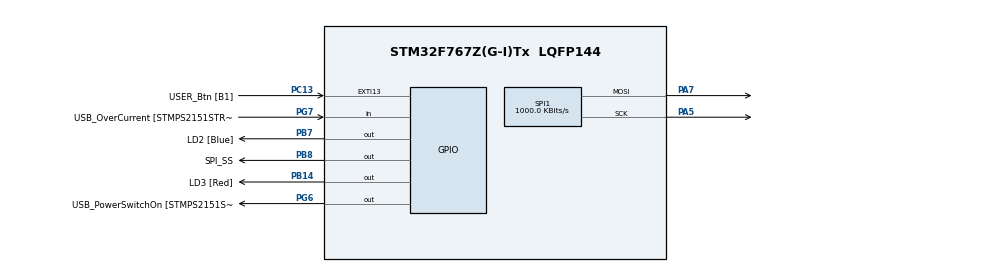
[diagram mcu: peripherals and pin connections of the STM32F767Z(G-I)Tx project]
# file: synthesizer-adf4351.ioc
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Mcu.Family=STM32F7
Mcu.Name=STM32F767Z(G-I)Tx
Mcu.Package=LQFP144
NVIC.PriorityGroup=NVIC_PRIORITYGROUP_4
PA1.GPIO_Label=RMII_REF_CLK [LAN8742A-CZ-TR_REFCLK0]
PA1.Signal=ETH_REF_CLK
PA10.GPIO_Label=USB_ID
PA10.Signal=USB_OTG_FS_ID
PA11.GPIO_Label=USB_DM
PA11.Signal=USB_OTG_FS_DM
PA12.GPIO_Label=USB_DP
PA12.Signal=USB_OTG_FS_DP
PA13.GPIO_Label=TMS
PA13.Signal=SYS_JTMS-SWDIO
PA14.GPIO_Label=TCK
PA14.Signal=SYS_JTCK-SWCLK
PA2.GPIO_Label=RMII_MDIO [LAN8742A-CZ-TR_MDIO]
PA2.Signal=ETH_MDIO
PA5.Mode=TX_Only_Simplex_Unidirect_Master
PA5.Signal=SPI1_SCK
PA7.Mode=TX_Only_Simplex_Unidirect_Master
PA7.Signal=SPI1_MOSI
PA8.GPIO_Label=USB_SOF [TP1]
PA8.Signal=USB_OTG_FS_SOF
PA9.GPIO_Label=USB_VBUS
PA9.Signal=USB_OTG_FS_VBUS
PB13.GPIO_Label=RMII_TXD1 [LAN8742A-CZ-TR_TXD1]
PB13.Signal=ETH_TXD1
PB14.GPIO_Label=LD3 [Red]
PB14.Signal=GPIO_Output
PB3.GPIO_Label=SW0
PB3.Signal=SYS_JTDO-SWO
PB7.GPIO_Label=LD2 [Blue]
PB7.Signal=GPIO_Output
PB8.GPIO_Label=SPI_SS
PB8.Signal=GPIO_Output
PC1.GPIO_Label=RMII_MDC [LAN8742A-CZ-TR_MDC]
PC1.Signal=ETH_MDC
PC13.GPIO_Label=USER_Btn [B1]
PC13.Signal=GPXTI13
PC14/OSC32_IN.Signal=RCC_OSC32_IN
PC15/OSC32_OUT.Signal=RCC_OSC32_OUT
PC4.GPIO_Label=RMII_RXD0 [LAN8742A-CZ-TR_RXD0]
PC4.Signal=ETH_RXD0
PC5.GPIO_Label=RMII_RXD1 [LAN8742A-CZ-TR_RXD1]
PC5.Signal=ETH_RXD1
PD8.GPIO_Label=STLK_RX [STM32F103CBT6_PA3]
PD8.Signal=USART3_TX
PD9.GPIO_Label=STLK_TX [STM32F103CBT6_PA2]
PD9.Signal=USART3_RX
PG11.GPIO_Label=RMII_TX_EN [LAN8742A-CZ-TR_TXEN]
PG11.Signal=ETH_TX_EN
PG13.GPIO_Label=RMII_TXD0 [LAN8742A-CZ-TR_TXD0]
PG13.Signal=ETH_TXD0
PG6.GPIO_Label=USB_PowerSwitchOn [STMPS2151STR_EN]
PG6.Signal=GPIO_Output
PG7.GPIO_Label=USB_OverCurrent [STMPS2151STR_FAULT]
PG7.Signal=GPIO_Input
PH0/OSC_IN.GPIO_Label=MCO [STM32F103CBT6_PA8]
PH0/OSC_IN.Mode=HSE-External-Clock-Source
PH0/OSC_IN.Signal=RCC_OSC_IN
PH1/OSC_OUT.Mode=HSE-External-Clock-Source
PH1/OSC_OUT.Signal=RCC_OSC_OUT
ProjectManager.HeapSize=0x200
ProjectManager.StackSize=0x400
ProjectManager.TargetToolchain=Makefile
RCC.48MHZClocksFreq_Value=24000000
RCC.AHBFreq_Value=8000000
RCC.APB1CLKDivider=RCC_HCLK_DIV2
RCC.APB1Freq_Value=4000000
RCC.APB1TimFreq_Value=8000000
RCC.APB2Freq_Value=8000000
RCC.APB2TimFreq_Value=8000000
RCC.CortexFreq_Value=8000000
RCC.HCLKFreq_Value=8000000
RCC.HSE_VALUE=8000000
RCC.HSI_VALUE=16000000
RCC.LSE_VALUE=32768
RCC.PLLMUL=RCC_PLL_MUL9
RCC.PLLSourceVirtual=RCC_PLLSOURCE_HSE
RCC.PRESCALERUSB=RCC_USBCLKSOURCE_PLL_DIV1_5
RCC.SYSCLKFreq_VALUE=8000000
RCC.SYSCLKSource=RCC_SYSCLKSOURCE_HSE
RCC.SYSCLKSourceVirtual=RCC_SYSCLKSOURCE_PLLCLK
RCC.USBFreq_Value=48000000
RCC.VCOOutputFreq_Value=96000000
SPI1.BaudRatePrescaler=SPI_BAUDRATEPRESCALER_8
SPI1.CalculateBaudRate=1000.0 KBits/s
SPI1.DataSize=SPI_DATASIZE_8BIT
SPI1.Direction=SPI_DIRECTION_2LINES
SPI1.FirstBit=SPI_FIRSTBIT_MSB
SPI1.Mode=SPI_MODE_MASTER
SPI1.TIMode=SPI_TIMODE_DISABLE
SPI1.VirtualType=VM_MASTER
board=NUCLEO-F767ZI

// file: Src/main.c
/**
  ******************************************************************************
  * File Name          : main.c
  * Description        : Main program body
  ******************************************************************************
  ** This notice applies to any and all portions of this file
  * that are not between comment pairs USER CODE BEGIN and
  * USER CODE END. Other portions of this file, whether
  * inserted by the user or by software development tools
  * are owned by their respective copyright owners.
  *
  * COPYRIGHT(c) 2017 STMicroelectronics
  *
  * Redistribution and use in source and binary forms, with or without modification,
  * are permitted provided that the following conditions are met:
  *   1. Redistributions of source code must retain the above copyright notice,
  *      this list of conditions and the following disclaimer.
  *   2. Redistributions in binary form must reproduce the above copyright notice,
  *      this list of conditions and the following disclaimer in the documentation
  *      and/or other materials provided with the distribution.
  *   3. Neither the name of STMicroelectronics nor the names of its contributors
  *      may be used to endorse or promote products derived from this software
  *      without specific prior written permission.
  *
  * THIS SOFTWARE IS PROVIDED BY THE COPYRIGHT HOLDERS AND CONTRIBUTORS "AS IS"
  * AND ANY EXPRESS OR IMPLIED WARRANTIES, INCLUDING, BUT NOT LIMITED TO, THE
  * IMPLIED WARRANTIES OF MERCHANTABILITY AND FITNESS FOR A PARTICULAR PURPOSE ARE
  * DISCLAIMED. IN NO EVENT SHALL THE COPYRIGHT HOLDER OR CONTRIBUTORS BE LIABLE
  * FOR ANY DIRECT, INDIRECT, INCIDENTAL, SPECIAL, EXEMPLARY, OR CONSEQUENTIAL
  * DAMAGES (INCLUDING, BUT NOT LIMITED TO, PROCUREMENT OF SUBSTITUTE GOODS OR
  * SERVICES; LOSS OF USE, DATA, OR PROFITS; OR BUSINESS INTERRUPTION) HOWEVER
  * CAUSED AND ON ANY THEORY OF LIABILITY, WHETHER IN CONTRACT, STRICT LIABILITY,
  * OR TORT (INCLUDING NEGLIGENCE OR OTHERWISE) ARISING IN ANY WAY OUT OF THE USE
  * OF THIS SOFTWARE, EVEN IF ADVISED OF THE POSSIBILITY OF SUCH DAMAGE.
  *
  ******************************************************************************
  */
#include "main.h"
#include "stm32f7xx_hal.h"

SPI_HandleTypeDef hspi1;

/* USER CODE BEGIN PV */
/* Private variables ---------------------------------------------------------*/

/* USER CODE END PV */

void SystemClock_Config(void);
static void MX_GPIO_Init(void);
static void MX_SPI1_Init(void);

/* USER CODE BEGIN PFP */
/* Private function prototypes -----------------------------------------------*/

static void synthesizer_ss_high() {
  HAL_GPIO_WritePin(SPI_SS_GPIO_Port, SPI_SS_Pin, GPIO_PIN_SET);
}

static void synthesizer_ss_low() {
  HAL_GPIO_WritePin(SPI_SS_GPIO_Port, SPI_SS_Pin, GPIO_PIN_RESET);
}

static void synthesizer_send_register(uint32_t data) {
  synthesizer_ss_low();
  HAL_SPI_Transmit(&hspi1, (uint8_t *)data, 32, 5 * 1000);
  synthesizer_ss_high();
}

static void synthesizer_set_registers(
  uint32_t r0,
  uint32_t r1,
  uint32_t r2,
  uint32_t r3,
  uint32_t r4,
  uint32_t r5) {

  synthesizer_send_register(r5);
  // synthesizer_send_register(r4);
  // synthesizer_send_register(r3);
  // synthesizer_send_register(r2);
  // synthesizer_send_register(r1);
  // synthesizer_send_register(r0);
}

/* USER CODE END PFP */

int main(void)
{

  /* MCU Configuration----------------------------------------------------------*/

  /* Reset of all peripherals, Initializes the Flash interface and the Systick. */
  HAL_Init();

  /* Configure the system clock */
  SystemClock_Config();

  /* Initialize all configured peripherals */
  MX_GPIO_Init();
  MX_SPI1_Init();

  /* USER CODE BEGIN 2 */

  // default high
  synthesizer_ss_high();

  /* USER CODE END 2 */

  /* Infinite loop */
  while (1)
  {

  /* USER CODE BEGIN 3 */

    synthesizer_set_registers(
      0x0400000,
      0x8008011,
      0x0004e42,
      0x00004b3,
      0x0ec803c,
      0x0580005);

    HAL_Delay(1);
  }
  /* USER CODE END 3 */

}

/** System Clock Configuration
*/
void SystemClock_Config(void)
{

  RCC_OscInitTypeDef RCC_OscInitStruct;
  RCC_ClkInitTypeDef RCC_ClkInitStruct;

    /**Configure the main internal regulator output voltage
    */
  __HAL_RCC_PWR_CLK_ENABLE();

  __HAL_PWR_VOLTAGESCALING_CONFIG(PWR_REGULATOR_VOLTAGE_SCALE3);

    /**Initializes the CPU, AHB and APB busses clocks
    */
  RCC_OscInitStruct.OscillatorType = RCC_OSCILLATORTYPE_HSE;
  RCC_OscInitStruct.HSEState = RCC_HSE_BYPASS;
  RCC_OscInitStruct.PLL.PLLState = RCC_PLL_NONE;
  if (HAL_RCC_OscConfig(&RCC_OscInitStruct) != HAL_OK)
  {
    _Error_Handler(__FILE__, __LINE__);
  }

    /**Initializes the CPU, AHB and APB busses clocks
    */
  RCC_ClkInitStruct.ClockType = RCC_CLOCKTYPE_HCLK|RCC_CLOCKTYPE_SYSCLK
                              |RCC_CLOCKTYPE_PCLK1|RCC_CLOCKTYPE_PCLK2;
  RCC_ClkInitStruct.SYSCLKSource = RCC_SYSCLKSOURCE_HSE;
  RCC_ClkInitStruct.AHBCLKDivider = RCC_SYSCLK_DIV256;
  RCC_ClkInitStruct.APB1CLKDivider = RCC_HCLK_DIV2;
  RCC_ClkInitStruct.APB2CLKDivider = RCC_HCLK_DIV1;

  if (HAL_RCC_ClockConfig(&RCC_ClkInitStruct, FLASH_LATENCY_0) != HAL_OK)
  {
    _Error_Handler(__FILE__, __LINE__);
  }

    /**Configure the Systick interrupt time
    */
  HAL_SYSTICK_Config(HAL_RCC_GetHCLKFreq()/1000);

    /**Configure the Systick
    */
  HAL_SYSTICK_CLKSourceConfig(SYSTICK_CLKSOURCE_HCLK);

  /* SysTick_IRQn interrupt configuration */
  HAL_NVIC_SetPriority(SysTick_IRQn, 0, 0);
}

/* SPI1 init function */
static void MX_SPI1_Init(void)
{

  /* SPI1 parameter configuration*/
  hspi1.Instance = SPI1;
  hspi1.Init.Mode = SPI_MODE_MASTER;
  hspi1.Init.Direction = SPI_DIRECTION_2LINES;
  hspi1.Init.DataSize = SPI_DATASIZE_8BIT;
  hspi1.Init.CLKPolarity = SPI_POLARITY_LOW;
  hspi1.Init.CLKPhase = SPI_PHASE_1EDGE;
  hspi1.Init.NSS = SPI_NSS_SOFT;
  hspi1.Init.BaudRatePrescaler = SPI_BAUDRATEPRESCALER_2;
  hspi1.Init.FirstBit = SPI_FIRSTBIT_MSB;
  hspi1.Init.TIMode = SPI_TIMODE_DISABLE;
  hspi1.Init.CRCCalculation = SPI_CRCCALCULATION_DISABLE;
  hspi1.Init.CRCPolynomial = 7;
  hspi1.Init.CRCLength = SPI_CRC_LENGTH_DATASIZE;
  hspi1.Init.NSSPMode = SPI_NSS_PULSE_ENABLE;
  if (HAL_SPI_Init(&hspi1) != HAL_OK)
  {
    _Error_Handler(__FILE__, __LINE__);
  }

}

/** Configure pins as
        * Analog
        * Input
        * Output
        * EVENT_OUT
        * EXTI
     PC1   ------> ETH_MDC
     PA1   ------> ETH_REF_CLK
     PA2   ------> ETH_MDIO
     PA7   ------> ETH_CRS_DV
     PC4   ------> ETH_RXD0
     PC5   ------> ETH_RXD1
     PB13   ------> ETH_TXD1
     PD8   ------> USART3_TX
     PD9   ------> USART3_RX
     PA8   ------> USB_OTG_FS_SOF
     PA9   ------> USB_OTG_FS_VBUS
     PA10   ------> USB_OTG_FS_ID
     PA11   ------> USB_OTG_FS_DM
     PA12   ------> USB_OTG_FS_DP
     PG11   ------> ETH_TX_EN
     PG13   ------> ETH_TXD0
*/
static void MX_GPIO_Init(void)
{

  GPIO_InitTypeDef GPIO_InitStruct;

  /* GPIO Ports Clock Enable */
  __HAL_RCC_GPIOC_CLK_ENABLE();
  __HAL_RCC_GPIOH_CLK_ENABLE();
  __HAL_RCC_GPIOA_CLK_ENABLE();
  __HAL_RCC_GPIOB_CLK_ENABLE();
  __HAL_RCC_GPIOD_CLK_ENABLE();
  __HAL_RCC_GPIOG_CLK_ENABLE();

  /*Configure GPIO pin Output Level */
  HAL_GPIO_WritePin(GPIOB, LD3_Pin|LD2_Pin|SPI_SS_Pin, GPIO_PIN_RESET);

  /*Configure GPIO pin Output Level */
  HAL_GPIO_WritePin(USB_PowerSwitchOn_GPIO_Port, USB_PowerSwitchOn_Pin, GPIO_PIN_RESET);

  /*Configure GPIO pin : USER_Btn_Pin */
  GPIO_InitStruct.Pin = USER_Btn_Pin;
  GPIO_InitStruct.Mode = GPIO_MODE_IT_RISING;
  GPIO_InitStruct.Pull = GPIO_NOPULL;
  HAL_GPIO_Init(USER_Btn_GPIO_Port, &GPIO_InitStruct);

  /*Configure GPIO pins : RMII_MDC_Pin RMII_RXD0_Pin RMII_RXD1_Pin */
  GPIO_InitStruct.Pin = RMII_MDC_Pin|RMII_RXD0_Pin|RMII_RXD1_Pin;
  GPIO_InitStruct.Mode = GPIO_MODE_AF_PP;
  GPIO_InitStruct.Pull = GPIO_NOPULL;
  GPIO_InitStruct.Speed = GPIO_SPEED_FREQ_VERY_HIGH;
  GPIO_InitStruct.Alternate = GPIO_AF11_ETH;
  HAL_GPIO_Init(GPIOC, &GPIO_InitStruct);

  /*Configure GPIO pins : RMII_REF_CLK_Pin RMII_MDIO_Pin RMII_CRS_DV_Pin */
  GPIO_InitStruct.Pin = RMII_REF_CLK_Pin|RMII_MDIO_Pin|RMII_CRS_DV_Pin;
  GPIO_InitStruct.Mode = GPIO_MODE_AF_PP;
  GPIO_InitStruct.Pull = GPIO_NOPULL;
  GPIO_InitStruct.Speed = GPIO_SPEED_FREQ_VERY_HIGH;
  GPIO_InitStruct.Alternate = GPIO_AF11_ETH;
  HAL_GPIO_Init(GPIOA, &GPIO_InitStruct);

  /*Configure GPIO pin : RMII_TXD1_Pin */
  GPIO_InitStruct.Pin = RMII_TXD1_Pin;
  GPIO_InitStruct.Mode = GPIO_MODE_AF_PP;
  GPIO_InitStruct.Pull = GPIO_NOPULL;
  GPIO_InitStruct.Speed = GPIO_SPEED_FREQ_VERY_HIGH;
  GPIO_InitStruct.Alternate = GPIO_AF11_ETH;
  HAL_GPIO_Init(RMII_TXD1_GPIO_Port, &GPIO_InitStruct);

  /*Configure GPIO pins : LD3_Pin LD2_Pin SPI_SS_Pin */
  GPIO_InitStruct.Pin = LD3_Pin|LD2_Pin|SPI_SS_Pin;
  GPIO_InitStruct.Mode = GPIO_MODE_OUTPUT_PP;
  GPIO_InitStruct.Pull = GPIO_NOPULL;
  GPIO_InitStruct.Speed = GPIO_SPEED_FREQ_LOW;
  HAL_GPIO_Init(GPIOB, &GPIO_InitStruct);

  /*Configure GPIO pins : STLK_RX_Pin STLK_TX_Pin */
  GPIO_InitStruct.Pin = STLK_RX_Pin|STLK_TX_Pin;
  GPIO_InitStruct.Mode = GPIO_MODE_AF_PP;
  GPIO_InitStruct.Pull = GPIO_NOPULL;
  GPIO_InitStruct.Speed = GPIO_SPEED_FREQ_VERY_HIGH;
  GPIO_InitStruct.Alternate = GPIO_AF7_USART3;
  HAL_GPIO_Init(GPIOD, &GPIO_InitStruct);

  /*Configure GPIO pin : USB_PowerSwitchOn_Pin */
  GPIO_InitStruct.Pin = USB_PowerSwitchOn_Pin;
  GPIO_InitStruct.Mode = GPIO_MODE_OUTPUT_PP;
  GPIO_InitStruct.Pull = GPIO_NOPULL;
  GPIO_InitStruct.Speed = GPIO_SPEED_FREQ_LOW;
  HAL_GPIO_Init(USB_PowerSwitchOn_GPIO_Port, &GPIO_InitStruct);

  /*Configure GPIO pin : USB_OverCurrent_Pin */
  GPIO_InitStruct.Pin = USB_OverCurrent_Pin;
  GPIO_InitStruct.Mode = GPIO_MODE_INPUT;
  GPIO_InitStruct.Pull = GPIO_NOPULL;
  HAL_GPIO_Init(USB_OverCurrent_GPIO_Port, &GPIO_InitStruct);

  /*Configure GPIO pins : USB_SOF_Pin USB_ID_Pin USB_DM_Pin USB_DP_Pin */
  GPIO_InitStruct.Pin = USB_SOF_Pin|USB_ID_Pin|USB_DM_Pin|USB_DP_Pin;
  GPIO_InitStruct.Mode = GPIO_MODE_AF_PP;
  GPIO_InitStruct.Pull = GPIO_NOPULL;
  GPIO_InitStruct.Speed = GPIO_SPEED_FREQ_VERY_HIGH;
  GPIO_InitStruct.Alternate = GPIO_AF10_OTG_FS;
  HAL_GPIO_Init(GPIOA, &GPIO_InitStruct);

  /*Configure GPIO pin : USB_VBUS_Pin */
  GPIO_InitStruct.Pin = USB_VBUS_Pin;
  GPIO_InitStruct.Mode = GPIO_MODE_INPUT;
  GPIO_InitStruct.Pull = GPIO_NOPULL;
  HAL_GPIO_Init(USB_VBUS_GPIO_Port, &GPIO_InitStruct);

  /*Configure GPIO pins : RMII_TX_EN_Pin RMII_TXD0_Pin */
  GPIO_InitStruct.Pin = RMII_TX_EN_Pin|RMII_TXD0_Pin;
  GPIO_InitStruct.Mode = GPIO_MODE_AF_PP;
  GPIO_InitStruct.Pull = GPIO_NOPULL;
  GPIO_InitStruct.Speed = GPIO_SPEED_FREQ_VERY_HIGH;
  GPIO_InitStruct.Alternate = GPIO_AF11_ETH;
  HAL_GPIO_Init(GPIOG, &GPIO_InitStruct);

}

void _Error_Handler(char * file, int line)
{
  while(1)
  {
  }
}

/************************ (C) COPYRIGHT STMicroelectronics *****END OF FILE****/
